# Generated by innovus_enablement/scripts/gen_fakeram.py: abstract 2048x39 SRAM.
# Geometry is an assumption (see script header), not PDK data.
VERSION 5.8 ;
BUSBITCHARS "[]" ;
DIVIDERCHAR "/" ;

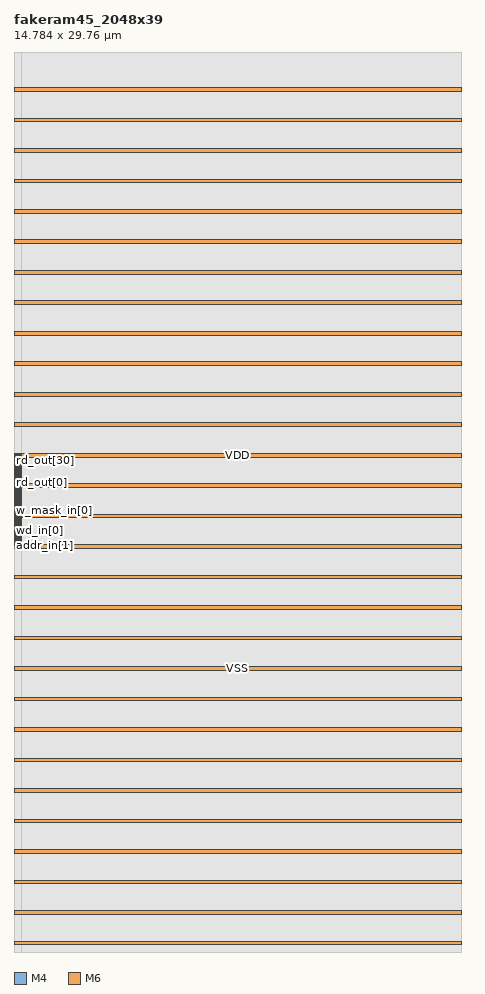
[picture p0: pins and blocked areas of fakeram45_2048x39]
MACRO fakeram45_2048x39
  CLASS BLOCK ;
  FOREIGN fakeram45_2048x39 0 0 ;
  ORIGIN 0 0 ;
  SIZE 14.7840 BY 29.7600 ;
  SYMMETRY X Y R90 ;
  PIN clk
    DIRECTION INPUT ;
    USE CLOCK ;
    PORT
      LAYER M4 ;
        RECT 0 13.3260 0.2400 13.3380 ;
    END
  END clk
  PIN ce_in
    DIRECTION INPUT ;
    USE SIGNAL ;
    PORT
      LAYER M4 ;
        RECT 0 13.3500 0.2400 13.3620 ;
    END
  END ce_in
  PIN we_in
    DIRECTION INPUT ;
    USE SIGNAL ;
    PORT
      LAYER M4 ;
        RECT 0 13.3740 0.2400 13.3860 ;
    END
  END we_in
  PIN addr_in[0]
    DIRECTION INPUT ;
    USE SIGNAL ;
    PORT
      LAYER M4 ;
        RECT 0 13.3980 0.2400 13.4100 ;
    END
  END addr_in[0]
  PIN addr_in[1]
    DIRECTION INPUT ;
    USE SIGNAL ;
    PORT
      LAYER M4 ;
        RECT 0 13.4220 0.2400 13.4340 ;
    END
  END addr_in[1]
  PIN addr_in[2]
    DIRECTION INPUT ;
    USE SIGNAL ;
    PORT
      LAYER M4 ;
        RECT 0 13.4460 0.2400 13.4580 ;
    END
  END addr_in[2]
  PIN addr_in[3]
    DIRECTION INPUT ;
    USE SIGNAL ;
    PORT
      LAYER M4 ;
        RECT 0 13.4700 0.2400 13.4820 ;
    END
  END addr_in[3]
  PIN addr_in[4]
    DIRECTION INPUT ;
    USE SIGNAL ;
    PORT
      LAYER M4 ;
        RECT 0 13.4940 0.2400 13.5060 ;
    END
  END addr_in[4]
  PIN addr_in[5]
    DIRECTION INPUT ;
    USE SIGNAL ;
    PORT
      LAYER M4 ;
        RECT 0 13.5180 0.2400 13.5300 ;
    END
  END addr_in[5]
  PIN addr_in[6]
    DIRECTION INPUT ;
    USE SIGNAL ;
    PORT
      LAYER M4 ;
        RECT 0 13.5420 0.2400 13.5540 ;
    END
  END addr_in[6]
  PIN addr_in[7]
    DIRECTION INPUT ;
    USE SIGNAL ;
    PORT
      LAYER M4 ;
        RECT 0 13.5660 0.2400 13.5780 ;
    END
  END addr_in[7]
  PIN addr_in[8]
    DIRECTION INPUT ;
    USE SIGNAL ;
    PORT
      LAYER M4 ;
        RECT 0 13.5900 0.2400 13.6020 ;
    END
  END addr_in[8]
  PIN addr_in[9]
    DIRECTION INPUT ;
    USE SIGNAL ;
    PORT
      LAYER M4 ;
        RECT 0 13.6140 0.2400 13.6260 ;
    END
  END addr_in[9]
  PIN addr_in[10]
    DIRECTION INPUT ;
    USE SIGNAL ;
    PORT
      LAYER M4 ;
        RECT 0 13.6380 0.2400 13.6500 ;
    END
  END addr_in[10]
  PIN wd_in[0]
    DIRECTION INPUT ;
    USE SIGNAL ;
    PORT
      LAYER M4 ;
        RECT 0 13.6620 0.2400 13.6740 ;
    END
  END wd_in[0]
  PIN wd_in[1]
    DIRECTION INPUT ;
    USE SIGNAL ;
    PORT
      LAYER M4 ;
        RECT 0 13.6860 0.2400 13.6980 ;
    END
  END wd_in[1]
  PIN wd_in[2]
    DIRECTION INPUT ;
    USE SIGNAL ;
    PORT
      LAYER M4 ;
        RECT 0 13.7100 0.2400 13.7220 ;
    END
  END wd_in[2]
  PIN wd_in[3]
    DIRECTION INPUT ;
    USE SIGNAL ;
    PORT
      LAYER M4 ;
        RECT 0 13.7340 0.2400 13.7460 ;
    END
  END wd_in[3]
  PIN wd_in[4]
    DIRECTION INPUT ;
    USE SIGNAL ;
    PORT
      LAYER M4 ;
        RECT 0 13.7580 0.2400 13.7700 ;
    END
  END wd_in[4]
  PIN wd_in[5]
    DIRECTION INPUT ;
    USE SIGNAL ;
    PORT
      LAYER M4 ;
        RECT 0 13.7820 0.2400 13.7940 ;
    END
  END wd_in[5]
  PIN wd_in[6]
    DIRECTION INPUT ;
    USE SIGNAL ;
    PORT
      LAYER M4 ;
        RECT 0 13.8060 0.2400 13.8180 ;
    END
  END wd_in[6]
  PIN wd_in[7]
    DIRECTION INPUT ;
    USE SIGNAL ;
    PORT
      LAYER M4 ;
        RECT 0 13.8300 0.2400 13.8420 ;
    END
  END wd_in[7]
  PIN wd_in[8]
    DIRECTION INPUT ;
    USE SIGNAL ;
    PORT
      LAYER M4 ;
        RECT 0 13.8540 0.2400 13.8660 ;
    END
  END wd_in[8]
  PIN wd_in[9]
    DIRECTION INPUT ;
    USE SIGNAL ;
    PORT
      LAYER M4 ;
        RECT 0 13.8780 0.2400 13.8900 ;
    END
  END wd_in[9]
  PIN wd_in[10]
    DIRECTION INPUT ;
    USE SIGNAL ;
    PORT
      LAYER M4 ;
        RECT 0 13.9020 0.2400 13.9140 ;
    END
  END wd_in[10]
  PIN wd_in[11]
    DIRECTION INPUT ;
    USE SIGNAL ;
    PORT
      LAYER M4 ;
        RECT 0 13.9260 0.2400 13.9380 ;
    END
  END wd_in[11]
  PIN wd_in[12]
    DIRECTION INPUT ;
    USE SIGNAL ;
    PORT
      LAYER M4 ;
        RECT 0 13.9500 0.2400 13.9620 ;
    END
  END wd_in[12]
  PIN wd_in[13]
    DIRECTION INPUT ;
    USE SIGNAL ;
    PORT
      LAYER M4 ;
        RECT 0 13.9740 0.2400 13.9860 ;
    END
  END wd_in[13]
  PIN wd_in[14]
    DIRECTION INPUT ;
    USE SIGNAL ;
    PORT
      LAYER M4 ;
        RECT 0 13.9980 0.2400 14.0100 ;
    END
  END wd_in[14]
  PIN wd_in[15]
    DIRECTION INPUT ;
    USE SIGNAL ;
    PORT
      LAYER M4 ;
        RECT 0 14.0220 0.2400 14.0340 ;
    END
  END wd_in[15]
  PIN wd_in[16]
    DIRECTION INPUT ;
    USE SIGNAL ;
    PORT
      LAYER M4 ;
        RECT 0 14.0460 0.2400 14.0580 ;
    END
  END wd_in[16]
  PIN wd_in[17]
    DIRECTION INPUT ;
    USE SIGNAL ;
    PORT
      LAYER M4 ;
        RECT 0 14.0700 0.2400 14.0820 ;
    END
  END wd_in[17]
  PIN wd_in[18]
    DIRECTION INPUT ;
    USE SIGNAL ;
    PORT
      LAYER M4 ;
        RECT 0 14.0940 0.2400 14.1060 ;
    END
  END wd_in[18]
  PIN wd_in[19]
    DIRECTION INPUT ;
    USE SIGNAL ;
    PORT
      LAYER M4 ;
        RECT 0 14.1180 0.2400 14.1300 ;
    END
  END wd_in[19]
  PIN wd_in[20]
    DIRECTION INPUT ;
    USE SIGNAL ;
    PORT
      LAYER M4 ;
        RECT 0 14.1420 0.2400 14.1540 ;
    END
  END wd_in[20]
  PIN wd_in[21]
    DIRECTION INPUT ;
    USE SIGNAL ;
    PORT
      LAYER M4 ;
        RECT 0 14.1660 0.2400 14.1780 ;
    END
  END wd_in[21]
  PIN wd_in[22]
    DIRECTION INPUT ;
    USE SIGNAL ;
    PORT
      LAYER M4 ;
        RECT 0 14.1900 0.2400 14.2020 ;
    END
  END wd_in[22]
  PIN wd_in[23]
    DIRECTION INPUT ;
    USE SIGNAL ;
    PORT
      LAYER M4 ;
        RECT 0 14.2140 0.2400 14.2260 ;
    END
  END wd_in[23]
  PIN wd_in[24]
    DIRECTION INPUT ;
    USE SIGNAL ;
    PORT
      LAYER M4 ;
        RECT 0 14.2380 0.2400 14.2500 ;
    END
  END wd_in[24]
  PIN wd_in[25]
    DIRECTION INPUT ;
    USE SIGNAL ;
    PORT
      LAYER M4 ;
        RECT 0 14.2620 0.2400 14.2740 ;
    END
  END wd_in[25]
  PIN wd_in[26]
    DIRECTION INPUT ;
    USE SIGNAL ;
    PORT
      LAYER M4 ;
        RECT 0 14.2860 0.2400 14.2980 ;
    END
  END wd_in[26]
  PIN wd_in[27]
    DIRECTION INPUT ;
    USE SIGNAL ;
    PORT
      LAYER M4 ;
        RECT 0 14.3100 0.2400 14.3220 ;
    END
  END wd_in[27]
  PIN wd_in[28]
    DIRECTION INPUT ;
    USE SIGNAL ;
    PORT
      LAYER M4 ;
        RECT 0 14.3340 0.2400 14.3460 ;
    END
  END wd_in[28]
  PIN wd_in[29]
    DIRECTION INPUT ;
    USE SIGNAL ;
    PORT
      LAYER M4 ;
        RECT 0 14.3580 0.2400 14.3700 ;
    END
  END wd_in[29]
  PIN wd_in[30]
    DIRECTION INPUT ;
    USE SIGNAL ;
    PORT
      LAYER M4 ;
        RECT 0 14.3820 0.2400 14.3940 ;
    END
  END wd_in[30]
  PIN wd_in[31]
    DIRECTION INPUT ;
    USE SIGNAL ;
    PORT
      LAYER M4 ;
        RECT 0 14.4060 0.2400 14.4180 ;
    END
  END wd_in[31]
  PIN wd_in[32]
    DIRECTION INPUT ;
    USE SIGNAL ;
    PORT
      LAYER M4 ;
        RECT 0 14.4300 0.2400 14.4420 ;
    END
  END wd_in[32]
  PIN wd_in[33]
    DIRECTION INPUT ;
    USE SIGNAL ;
    PORT
      LAYER M4 ;
        RECT 0 14.4540 0.2400 14.4660 ;
    END
  END wd_in[33]
  PIN wd_in[34]
    DIRECTION INPUT ;
    USE SIGNAL ;
    PORT
      LAYER M4 ;
        RECT 0 14.4780 0.2400 14.4900 ;
    END
  END wd_in[34]
  PIN wd_in[35]
    DIRECTION INPUT ;
    USE SIGNAL ;
    PORT
      LAYER M4 ;
        RECT 0 14.5020 0.2400 14.5140 ;
    END
  END wd_in[35]
  PIN wd_in[36]
    DIRECTION INPUT ;
    USE SIGNAL ;
    PORT
      LAYER M4 ;
        RECT 0 14.5260 0.2400 14.5380 ;
    END
  END wd_in[36]
  PIN wd_in[37]
    DIRECTION INPUT ;
    USE SIGNAL ;
    PORT
      LAYER M4 ;
        RECT 0 14.5500 0.2400 14.5620 ;
    END
  END wd_in[37]
  PIN wd_in[38]
    DIRECTION INPUT ;
    USE SIGNAL ;
    PORT
      LAYER M4 ;
        RECT 0 14.5740 0.2400 14.5860 ;
    END
  END wd_in[38]
  PIN w_mask_in[0]
    DIRECTION INPUT ;
    USE SIGNAL ;
    PORT
      LAYER M4 ;
        RECT 0 14.5980 0.2400 14.6100 ;
    END
  END w_mask_in[0]
  PIN w_mask_in[1]
    DIRECTION INPUT ;
    USE SIGNAL ;
    PORT
      LAYER M4 ;
        RECT 0 14.6220 0.2400 14.6340 ;
    END
  END w_mask_in[1]
  PIN w_mask_in[2]
    DIRECTION INPUT ;
    USE SIGNAL ;
    PORT
      LAYER M4 ;
        RECT 0 14.6460 0.2400 14.6580 ;
    END
  END w_mask_in[2]
  PIN w_mask_in[3]
    DIRECTION INPUT ;
    USE SIGNAL ;
    PORT
      LAYER M4 ;
        RECT 0 14.6700 0.2400 14.6820 ;
    END
  END w_mask_in[3]
  PIN w_mask_in[4]
    DIRECTION INPUT ;
    USE SIGNAL ;
    PORT
      LAYER M4 ;
        RECT 0 14.6940 0.2400 14.7060 ;
    END
  END w_mask_in[4]
  PIN w_mask_in[5]
    DIRECTION INPUT ;
    USE SIGNAL ;
    PORT
      LAYER M4 ;
        RECT 0 14.7180 0.2400 14.7300 ;
    END
  END w_mask_in[5]
  PIN w_mask_in[6]
    DIRECTION INPUT ;
    USE SIGNAL ;
    PORT
      LAYER M4 ;
        RECT 0 14.7420 0.2400 14.7540 ;
    END
  END w_mask_in[6]
  PIN w_mask_in[7]
    DIRECTION INPUT ;
    USE SIGNAL ;
    PORT
      LAYER M4 ;
        RECT 0 14.7660 0.2400 14.7780 ;
    END
  END w_mask_in[7]
  PIN w_mask_in[8]
    DIRECTION INPUT ;
    USE SIGNAL ;
    PORT
      LAYER M4 ;
        RECT 0 14.7900 0.2400 14.8020 ;
    END
  END w_mask_in[8]
  PIN w_mask_in[9]
    DIRECTION INPUT ;
    USE SIGNAL ;
    PORT
      LAYER M4 ;
        RECT 0 14.8140 0.2400 14.8260 ;
    END
  END w_mask_in[9]
  PIN w_mask_in[10]
    DIRECTION INPUT ;
    USE SIGNAL ;
    PORT
      LAYER M4 ;
        RECT 0 14.8380 0.2400 14.8500 ;
    END
  END w_mask_in[10]
  PIN w_mask_in[11]
    DIRECTION INPUT ;
    USE SIGNAL ;
    PORT
      LAYER M4 ;
        RECT 0 14.8620 0.2400 14.8740 ;
    END
  END w_mask_in[11]
  PIN w_mask_in[12]
    DIRECTION INPUT ;
    USE SIGNAL ;
    PORT
      LAYER M4 ;
        RECT 0 14.8860 0.2400 14.8980 ;
    END
  END w_mask_in[12]
  PIN w_mask_in[13]
    DIRECTION INPUT ;
    USE SIGNAL ;
    PORT
      LAYER M4 ;
        RECT 0 14.9100 0.2400 14.9220 ;
    END
  END w_mask_in[13]
  PIN w_mask_in[14]
    DIRECTION INPUT ;
    USE SIGNAL ;
    PORT
      LAYER M4 ;
        RECT 0 14.9340 0.2400 14.9460 ;
    END
  END w_mask_in[14]
  PIN w_mask_in[15]
    DIRECTION INPUT ;
    USE SIGNAL ;
    PORT
      LAYER M4 ;
        RECT 0 14.9580 0.2400 14.9700 ;
    END
  END w_mask_in[15]
  PIN w_mask_in[16]
    DIRECTION INPUT ;
    USE SIGNAL ;
    PORT
      LAYER M4 ;
        RECT 0 14.9820 0.2400 14.9940 ;
    END
  END w_mask_in[16]
  PIN w_mask_in[17]
    DIRECTION INPUT ;
    USE SIGNAL ;
    PORT
      LAYER M4 ;
        RECT 0 15.0060 0.2400 15.0180 ;
    END
  END w_mask_in[17]
  PIN w_mask_in[18]
    DIRECTION INPUT ;
    USE SIGNAL ;
    PORT
      LAYER M4 ;
        RECT 0 15.0300 0.2400 15.0420 ;
    END
  END w_mask_in[18]
  PIN w_mask_in[19]
    DIRECTION INPUT ;
    USE SIGNAL ;
    PORT
      LAYER M4 ;
        RECT 0 15.0540 0.2400 15.0660 ;
    END
  END w_mask_in[19]
  PIN w_mask_in[20]
    DIRECTION INPUT ;
    USE SIGNAL ;
    PORT
      LAYER M4 ;
        RECT 0 15.0780 0.2400 15.0900 ;
    END
  END w_mask_in[20]
  PIN w_mask_in[21]
    DIRECTION INPUT ;
    USE SIGNAL ;
    PORT
      LAYER M4 ;
        RECT 0 15.1020 0.2400 15.1140 ;
    END
  END w_mask_in[21]
  PIN w_mask_in[22]
    DIRECTION INPUT ;
    USE SIGNAL ;
    PORT
      LAYER M4 ;
        RECT 0 15.1260 0.2400 15.1380 ;
    END
  END w_mask_in[22]
  PIN w_mask_in[23]
    DIRECTION INPUT ;
    USE SIGNAL ;
    PORT
      LAYER M4 ;
        RECT 0 15.1500 0.2400 15.1620 ;
    END
  END w_mask_in[23]
  PIN w_mask_in[24]
    DIRECTION INPUT ;
    USE SIGNAL ;
    PORT
      LAYER M4 ;
        RECT 0 15.1740 0.2400 15.1860 ;
    END
  END w_mask_in[24]
  PIN w_mask_in[25]
    DIRECTION INPUT ;
    USE SIGNAL ;
    PORT
      LAYER M4 ;
        RECT 0 15.1980 0.2400 15.2100 ;
    END
  END w_mask_in[25]
  PIN w_mask_in[26]
    DIRECTION INPUT ;
    USE SIGNAL ;
    PORT
      LAYER M4 ;
        RECT 0 15.2220 0.2400 15.2340 ;
    END
  END w_mask_in[26]
  PIN w_mask_in[27]
    DIRECTION INPUT ;
    USE SIGNAL ;
    PORT
      LAYER M4 ;
        RECT 0 15.2460 0.2400 15.2580 ;
    END
  END w_mask_in[27]
  PIN w_mask_in[28]
    DIRECTION INPUT ;
    USE SIGNAL ;
    PORT
      LAYER M4 ;
        RECT 0 15.2700 0.2400 15.2820 ;
    END
  END w_mask_in[28]
  PIN w_mask_in[29]
    DIRECTION INPUT ;
    USE SIGNAL ;
    PORT
      LAYER M4 ;
        RECT 0 15.2940 0.2400 15.3060 ;
    END
  END w_mask_in[29]
  PIN w_mask_in[30]
    DIRECTION INPUT ;
    USE SIGNAL ;
    PORT
      LAYER M4 ;
        RECT 0 15.3180 0.2400 15.3300 ;
    END
  END w_mask_in[30]
  PIN w_mask_in[31]
    DIRECTION INPUT ;
    USE SIGNAL ;
    PORT
      LAYER M4 ;
        RECT 0 15.3420 0.2400 15.3540 ;
    END
  END w_mask_in[31]
  PIN w_mask_in[32]
    DIRECTION INPUT ;
    USE SIGNAL ;
    PORT
      LAYER M4 ;
        RECT 0 15.3660 0.2400 15.3780 ;
    END
  END w_mask_in[32]
  PIN w_mask_in[33]
    DIRECTION INPUT ;
    USE SIGNAL ;
    PORT
      LAYER M4 ;
        RECT 0 15.3900 0.2400 15.4020 ;
    END
  END w_mask_in[33]
  PIN w_mask_in[34]
    DIRECTION INPUT ;
    USE SIGNAL ;
    PORT
      LAYER M4 ;
        RECT 0 15.4140 0.2400 15.4260 ;
    END
  END w_mask_in[34]
  PIN w_mask_in[35]
    DIRECTION INPUT ;
    USE SIGNAL ;
    PORT
      LAYER M4 ;
        RECT 0 15.4380 0.2400 15.4500 ;
    END
  END w_mask_in[35]
  PIN w_mask_in[36]
    DIRECTION INPUT ;
    USE SIGNAL ;
    PORT
      LAYER M4 ;
        RECT 0 15.4620 0.2400 15.4740 ;
    END
  END w_mask_in[36]
  PIN w_mask_in[37]
    DIRECTION INPUT ;
    USE SIGNAL ;
    PORT
      LAYER M4 ;
        RECT 0 15.4860 0.2400 15.4980 ;
    END
  END w_mask_in[37]
  PIN w_mask_in[38]
    DIRECTION INPUT ;
    USE SIGNAL ;
    PORT
      LAYER M4 ;
        RECT 0 15.5100 0.2400 15.5220 ;
    END
  END w_mask_in[38]
  PIN rd_out[0]
    DIRECTION OUTPUT ;
    USE SIGNAL ;
    PORT
      LAYER M4 ;
        RECT 0 15.5340 0.2400 15.5460 ;
    END
  END rd_out[0]
  PIN rd_out[1]
    DIRECTION OUTPUT ;
    USE SIGNAL ;
    PORT
      LAYER M4 ;
        RECT 0 15.5580 0.2400 15.5700 ;
    END
  END rd_out[1]
  PIN rd_out[2]
    DIRECTION OUTPUT ;
    USE SIGNAL ;
    PORT
      LAYER M4 ;
        RECT 0 15.5820 0.2400 15.5940 ;
    END
  END rd_out[2]
  PIN rd_out[3]
    DIRECTION OUTPUT ;
    USE SIGNAL ;
    PORT
      LAYER M4 ;
        RECT 0 15.6060 0.2400 15.6180 ;
    END
  END rd_out[3]
  PIN rd_out[4]
    DIRECTION OUTPUT ;
    USE SIGNAL ;
    PORT
      LAYER M4 ;
        RECT 0 15.6300 0.2400 15.6420 ;
    END
  END rd_out[4]
  PIN rd_out[5]
    DIRECTION OUTPUT ;
    USE SIGNAL ;
    PORT
      LAYER M4 ;
        RECT 0 15.6540 0.2400 15.6660 ;
    END
  END rd_out[5]
  PIN rd_out[6]
    DIRECTION OUTPUT ;
    USE SIGNAL ;
    PORT
      LAYER M4 ;
        RECT 0 15.6780 0.2400 15.6900 ;
    END
  END rd_out[6]
  PIN rd_out[7]
    DIRECTION OUTPUT ;
    USE SIGNAL ;
    PORT
      LAYER M4 ;
        RECT 0 15.7020 0.2400 15.7140 ;
    END
  END rd_out[7]
  PIN rd_out[8]
    DIRECTION OUTPUT ;
    USE SIGNAL ;
    PORT
      LAYER M4 ;
        RECT 0 15.7260 0.2400 15.7380 ;
    END
  END rd_out[8]
  PIN rd_out[9]
    DIRECTION OUTPUT ;
    USE SIGNAL ;
    PORT
      LAYER M4 ;
        RECT 0 15.7500 0.2400 15.7620 ;
    END
  END rd_out[9]
  PIN rd_out[10]
    DIRECTION OUTPUT ;
    USE SIGNAL ;
    PORT
      LAYER M4 ;
        RECT 0 15.7740 0.2400 15.7860 ;
    END
  END rd_out[10]
  PIN rd_out[11]
    DIRECTION OUTPUT ;
    USE SIGNAL ;
    PORT
      LAYER M4 ;
        RECT 0 15.7980 0.2400 15.8100 ;
    END
  END rd_out[11]
  PIN rd_out[12]
    DIRECTION OUTPUT ;
    USE SIGNAL ;
    PORT
      LAYER M4 ;
        RECT 0 15.8220 0.2400 15.8340 ;
    END
  END rd_out[12]
  PIN rd_out[13]
    DIRECTION OUTPUT ;
    USE SIGNAL ;
    PORT
      LAYER M4 ;
        RECT 0 15.8460 0.2400 15.8580 ;
    END
  END rd_out[13]
  PIN rd_out[14]
    DIRECTION OUTPUT ;
    USE SIGNAL ;
    PORT
      LAYER M4 ;
        RECT 0 15.8700 0.2400 15.8820 ;
    END
  END rd_out[14]
  PIN rd_out[15]
    DIRECTION OUTPUT ;
    USE SIGNAL ;
    PORT
      LAYER M4 ;
        RECT 0 15.8940 0.2400 15.9060 ;
    END
  END rd_out[15]
  PIN rd_out[16]
    DIRECTION OUTPUT ;
    USE SIGNAL ;
    PORT
      LAYER M4 ;
        RECT 0 15.9180 0.2400 15.9300 ;
    END
  END rd_out[16]
  PIN rd_out[17]
    DIRECTION OUTPUT ;
    USE SIGNAL ;
    PORT
      LAYER M4 ;
        RECT 0 15.9420 0.2400 15.9540 ;
    END
  END rd_out[17]
  PIN rd_out[18]
    DIRECTION OUTPUT ;
    USE SIGNAL ;
    PORT
      LAYER M4 ;
        RECT 0 15.9660 0.2400 15.9780 ;
    END
  END rd_out[18]
  PIN rd_out[19]
    DIRECTION OUTPUT ;
    USE SIGNAL ;
    PORT
      LAYER M4 ;
        RECT 0 15.9900 0.2400 16.0020 ;
    END
  END rd_out[19]
  PIN rd_out[20]
    DIRECTION OUTPUT ;
    USE SIGNAL ;
    PORT
      LAYER M4 ;
        RECT 0 16.0140 0.2400 16.0260 ;
    END
  END rd_out[20]
  PIN rd_out[21]
    DIRECTION OUTPUT ;
    USE SIGNAL ;
    PORT
      LAYER M4 ;
        RECT 0 16.0380 0.2400 16.0500 ;
    END
  END rd_out[21]
  PIN rd_out[22]
    DIRECTION OUTPUT ;
    USE SIGNAL ;
    PORT
      LAYER M4 ;
        RECT 0 16.0620 0.2400 16.0740 ;
    END
  END rd_out[22]
  PIN rd_out[23]
    DIRECTION OUTPUT ;
    USE SIGNAL ;
    PORT
      LAYER M4 ;
        RECT 0 16.0860 0.2400 16.0980 ;
    END
  END rd_out[23]
  PIN rd_out[24]
    DIRECTION OUTPUT ;
    USE SIGNAL ;
    PORT
      LAYER M4 ;
        RECT 0 16.1100 0.2400 16.1220 ;
    END
  END rd_out[24]
  PIN rd_out[25]
    DIRECTION OUTPUT ;
    USE SIGNAL ;
    PORT
      LAYER M4 ;
        RECT 0 16.1340 0.2400 16.1460 ;
    END
  END rd_out[25]
  PIN rd_out[26]
    DIRECTION OUTPUT ;
    USE SIGNAL ;
    PORT
      LAYER M4 ;
        RECT 0 16.1580 0.2400 16.1700 ;
    END
  END rd_out[26]
  PIN rd_out[27]
    DIRECTION OUTPUT ;
    USE SIGNAL ;
    PORT
      LAYER M4 ;
        RECT 0 16.1820 0.2400 16.1940 ;
    END
  END rd_out[27]
  PIN rd_out[28]
    DIRECTION OUTPUT ;
    USE SIGNAL ;
    PORT
      LAYER M4 ;
        RECT 0 16.2060 0.2400 16.2180 ;
    END
  END rd_out[28]
  PIN rd_out[29]
    DIRECTION OUTPUT ;
    USE SIGNAL ;
    PORT
      LAYER M4 ;
        RECT 0 16.2300 0.2400 16.2420 ;
    END
  END rd_out[29]
  PIN rd_out[30]
    DIRECTION OUTPUT ;
    USE SIGNAL ;
    PORT
      LAYER M4 ;
        RECT 0 16.2540 0.2400 16.2660 ;
    END
  END rd_out[30]
  PIN rd_out[31]
    DIRECTION OUTPUT ;
    USE SIGNAL ;
    PORT
      LAYER M4 ;
        RECT 0 16.2780 0.2400 16.2900 ;
    END
  END rd_out[31]
  PIN rd_out[32]
    DIRECTION OUTPUT ;
    USE SIGNAL ;
    PORT
      LAYER M4 ;
        RECT 0 16.3020 0.2400 16.3140 ;
    END
  END rd_out[32]
  PIN rd_out[33]
    DIRECTION OUTPUT ;
    USE SIGNAL ;
    PORT
      LAYER M4 ;
        RECT 0 16.3260 0.2400 16.3380 ;
    END
  END rd_out[33]
  PIN rd_out[34]
    DIRECTION OUTPUT ;
    USE SIGNAL ;
    PORT
      LAYER M4 ;
        RECT 0 16.3500 0.2400 16.3620 ;
    END
  END rd_out[34]
  PIN rd_out[35]
    DIRECTION OUTPUT ;
    USE SIGNAL ;
    PORT
      LAYER M4 ;
        RECT 0 16.3740 0.2400 16.3860 ;
    END
  END rd_out[35]
  PIN rd_out[36]
    DIRECTION OUTPUT ;
    USE SIGNAL ;
    PORT
      LAYER M4 ;
        RECT 0 16.3980 0.2400 16.4100 ;
    END
  END rd_out[36]
  PIN rd_out[37]
    DIRECTION OUTPUT ;
    USE SIGNAL ;
    PORT
      LAYER M4 ;
        RECT 0 16.4220 0.2400 16.4340 ;
    END
  END rd_out[37]
  PIN rd_out[38]
    DIRECTION OUTPUT ;
    USE SIGNAL ;
    PORT
      LAYER M4 ;
        RECT 0 16.4460 0.2400 16.4580 ;
    END
  END rd_out[38]
  PIN VDD
    DIRECTION INOUT ;
    USE POWER ;
    PORT
      LAYER M6 ;
        RECT 0 0.2400 14.7840 0.3600 ;
        RECT 0 2.2560 14.7840 2.3760 ;
        RECT 0 4.2720 14.7840 4.3920 ;
        RECT 0 6.2880 14.7840 6.4080 ;
        RECT 0 8.3040 14.7840 8.4240 ;
        RECT 0 10.3200 14.7840 10.4400 ;
        RECT 0 12.3360 14.7840 12.4560 ;
        RECT 0 14.3520 14.7840 14.4720 ;
        RECT 0 16.3680 14.7840 16.4880 ;
        RECT 0 18.3840 14.7840 18.5040 ;
        RECT 0 20.4000 14.7840 20.5200 ;
        RECT 0 22.4160 14.7840 22.5360 ;
        RECT 0 24.4320 14.7840 24.5520 ;
        RECT 0 26.4480 14.7840 26.5680 ;
        RECT 0 28.4640 14.7840 28.5840 ;
    END
  END VDD
  PIN VSS
    DIRECTION INOUT ;
    USE GROUND ;
    PORT
      LAYER M6 ;
        RECT 0 1.2480 14.7840 1.3680 ;
        RECT 0 3.2640 14.7840 3.3840 ;
        RECT 0 5.2800 14.7840 5.4000 ;
        RECT 0 7.2960 14.7840 7.4160 ;
        RECT 0 9.3120 14.7840 9.4320 ;
        RECT 0 11.3280 14.7840 11.4480 ;
        RECT 0 13.3440 14.7840 13.4640 ;
        RECT 0 15.3600 14.7840 15.4800 ;
        RECT 0 17.3760 14.7840 17.4960 ;
        RECT 0 19.3920 14.7840 19.5120 ;
        RECT 0 21.4080 14.7840 21.5280 ;
        RECT 0 23.4240 14.7840 23.5440 ;
        RECT 0 25.4400 14.7840 25.5600 ;
        RECT 0 27.4560 14.7840 27.5760 ;
    END
  END VSS
  OBS
    LAYER M0 ;
      RECT 0 0 14.7840 29.7600 ;
    LAYER M1 ;
      RECT 0 0 14.7840 29.7600 ;
    LAYER M2 ;
      RECT 0 0 14.7840 29.7600 ;
    LAYER M3 ;
      RECT 0 0 14.7840 29.7600 ;
    LAYER VIA0 ;
      RECT 0 0 14.7840 29.7600 ;
    LAYER VIA1 ;
      RECT 0 0 14.7840 29.7600 ;
    LAYER VIA2 ;
      RECT 0 0 14.7840 29.7600 ;
    LAYER VIA3 ;
      RECT 0 0 14.7840 29.7600 ;
    LAYER M4 ;
      RECT 0.2640 0 14.7840 29.7600 ;
  END
END fakeram45_2048x39

END LIBRARY
